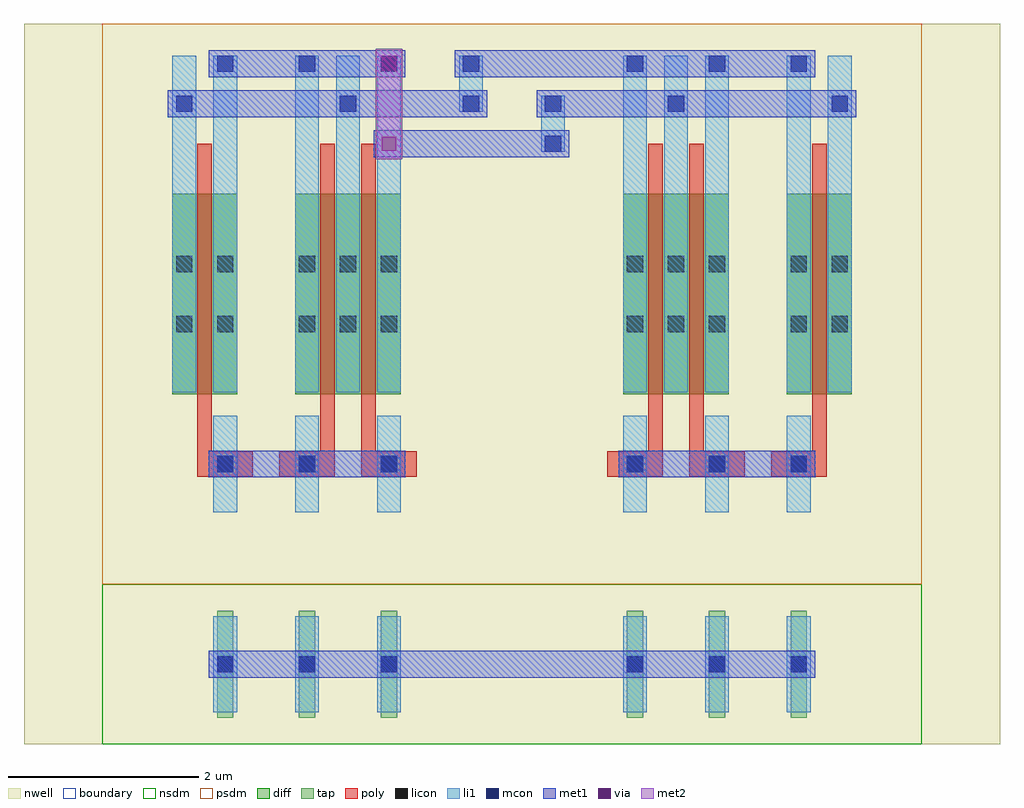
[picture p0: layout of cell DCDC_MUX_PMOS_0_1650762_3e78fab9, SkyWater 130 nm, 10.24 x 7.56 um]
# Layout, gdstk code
from math import pi, radians
import gdstk
lib = gdstk.Library(unit=1e-6, precision=1e-09)
def R(c, l, rs):  # rectangles x0, y0, x1, y1
    for r in rs: c.add(gdstk.rectangle(r[:2], r[2:], *l))
def A(c, l, x, y, w, h, nx, ny, dx, dy):  # array of equal rectangles
    R(c, l, [(x+i*dx, y+j*dy, x+i*dx+w, y+j*dy+h) for i in range(nx) for j in range(ny)])
def P(c, l, *ps):  # polygons
    for p in ps: c.add(gdstk.Polygon(p, *l))
nwell = (64, 20)
diff = (65, 20)
tap = (65, 44)
poly = (66, 20)
licon = (66, 44)
li1 = (67, 20)
mcon = (67, 44)
met1 = (68, 20)
via = (68, 44)
met2 = (69, 20)
nsdm = (93, 44)
psdm = (94, 20)
boundary = (235, 4)

pmos_4t_84335382_x3_y1__ = lib.new_cell('PMOS_4T_84335382_X3_Y1__e3cfcdb4')
R(pmos_4t_84335382_x3_y1__, nwell, [(0,0,5.12,7.56)])
R(pmos_4t_84335382_x3_y1__, diff, [(1.165,1.785,2.275,3.885), (2.885,1.785,3.565,3.885)])
A(pmos_4t_84335382_x3_y1__, tap, 1.205, 6.16, 0.17, 1.12, 3, 1, 0.86, 0)
A(pmos_4t_84335382_x3_y1__, poly, 1, 4.485, 0.58, 0.27, 3, 1, 0.86, 0)
R(pmos_4t_84335382_x3_y1__, poly, [(1.43,1.26,1.58,4.62), (1.86,1.26,2.01,4.62), (3.15,1.26,3.3,4.62)])
A(pmos_4t_84335382_x3_y1__, licon, 1.205, 4.535, 0.17, 0.17, 3, 2, 0.86, 2.1)
R(pmos_4t_84335382_x3_y1__, licon, [(1.205,2.435,1.375,2.605), (1.635,2.435,1.805,2.605), (1.635,2.435,1.805,2.605), (2.065,2.435,2.235,2.605), (2.925,2.435,3.095,2.605), (3.355,2.435,3.525,2.605), (1.205,3.065,1.375,3.235), (1.635,3.065,1.805,3.235), (1.635,3.065,1.805,3.235), (2.065,3.065,2.235,3.235), (2.925,3.065,3.095,3.235), (3.355,3.065,3.525,3.235)])
A(pmos_4t_84335382_x3_y1__, li1, 1.165, 0.335, 0.25, 3.53, 3, 1, 0.43, 0)
A(pmos_4t_84335382_x3_y1__, li1, 1.165, 4.115, 0.25, 1.01, 3, 2, 0.86, 2.1)
R(pmos_4t_84335382_x3_y1__, li1, [(2.885,0.335,3.135,3.865), (3.315,0.335,3.565,3.865)])
A(pmos_4t_84335382_x3_y1__, mcon, 1.205, 0.335, 0.17, 0.17, 3, 2, 0.86, 4.2)
A(pmos_4t_84335382_x3_y1__, mcon, 1.205, 6.635, 0.17, 0.17, 3, 1, 0.86, 0)
R(pmos_4t_84335382_x3_y1__, mcon, [(1.635,0.755,1.805,0.925), (3.355,0.755,3.525,0.925)])
R(pmos_4t_84335382_x3_y1__, met1, [(1.12,0.28,3.18,0.56), (0.69,0.7,3.61,0.98), (1.12,4.48,3.18,4.76), (1.12,6.58,3.18,6.86)])
R(pmos_4t_84335382_x3_y1__, nsdm, [(0,5.88,4.3,7.56)])
R(pmos_4t_84335382_x3_y1__, psdm, [(0,0,4.3,5.88)])

dcdc_mux_pmos_0_1650762_ = lib.new_cell('DCDC_MUX_PMOS_0_1650762_3e78fab9')
R(dcdc_mux_pmos_0_1650762_, li1, [(4.605,6.215,4.855,6.385), (4.605,6.215,4.855,6.385), (4.605,6.3,4.855,6.72), (3.745,6.635,3.995,6.805), (3.745,6.635,3.995,6.805), (4.605,6.635,4.855,6.805), (4.605,6.635,4.855,6.805), (3.745,6.72,3.995,7.14), (3.745,7.055,3.995,7.225), (3.745,7.055,3.995,7.225)])
R(dcdc_mux_pmos_0_1650762_, mcon, [(4.645,6.215,4.815,6.385), (4.645,6.215,4.815,6.385), (3.785,6.635,3.955,6.805), (3.785,6.635,3.955,6.805), (4.645,6.635,4.815,6.805), (4.645,6.635,4.815,6.805), (3.785,7.055,3.955,7.225), (3.785,7.055,3.955,7.225)])
R(dcdc_mux_pmos_0_1650762_, met1, [(3.01,0.7,5.59,0.98), (2.85,6.16,3.17,6.44), (2.85,6.16,3.17,6.44), (3.01,6.16,4.73,6.44), (4.56,6.16,4.9,6.44), (4.56,6.16,4.9,6.44), (3.44,6.58,3.87,6.86), (3.7,6.58,4.04,6.86), (3.7,6.58,4.04,6.86), (4.56,6.58,4.9,6.86), (4.56,6.58,4.9,6.86), (4.73,6.58,5.16,6.86), (2.85,7,3.17,7.28), (2.85,7,3.17,7.28), (3.7,7,4.04,7.28), (3.7,7,4.04,7.28), (3.87,7,5.59,7.28)])
P(dcdc_mux_pmos_0_1650762_, met1, [(0,0),(0,0),(0,0),(0,0)],
  [(0,0),(0,0),(0,0),(0,0)],
  [(0,0),(0,0),(0,0),(0,0)],
  [(0,0),(0,0),(0,0),(0,0)],
  [(0,0),(0,0),(0,0),(0,0)],
  [(0,0),(0,0),(0,0),(0,0)],
  [(0,0),(0,0),(0,0),(0,0)],
  [(0,0),(0,0),(0,0),(0,0)])
R(dcdc_mux_pmos_0_1650762_, via, [(2.935,6.225,3.085,6.375), (2.935,6.225,3.085,6.375), (2.935,7.065,3.085,7.215), (2.935,7.065,3.085,7.215)])
R(dcdc_mux_pmos_0_1650762_, met2, [(2.87,6.14,3.15,6.46), (2.87,6.14,3.15,6.46), (2.87,6.3,3.15,7.14), (2.87,6.98,3.15,7.3), (2.87,6.98,3.15,7.3)])
R(dcdc_mux_pmos_0_1650762_, boundary, [(0,0,8.6,7.56)])
dcdc_mux_pmos_0_1650762_.add(gdstk.Reference(pmos_4t_84335382_x3_y1__, (4.3,7.56), x_reflection=True))
dcdc_mux_pmos_0_1650762_.add(gdstk.Reference(pmos_4t_84335382_x3_y1__, (4.3,7.56), rotation=pi))

lib.write_gds('DCDC_MUX_PMOS_0_1650762_3e78fab9.gds')
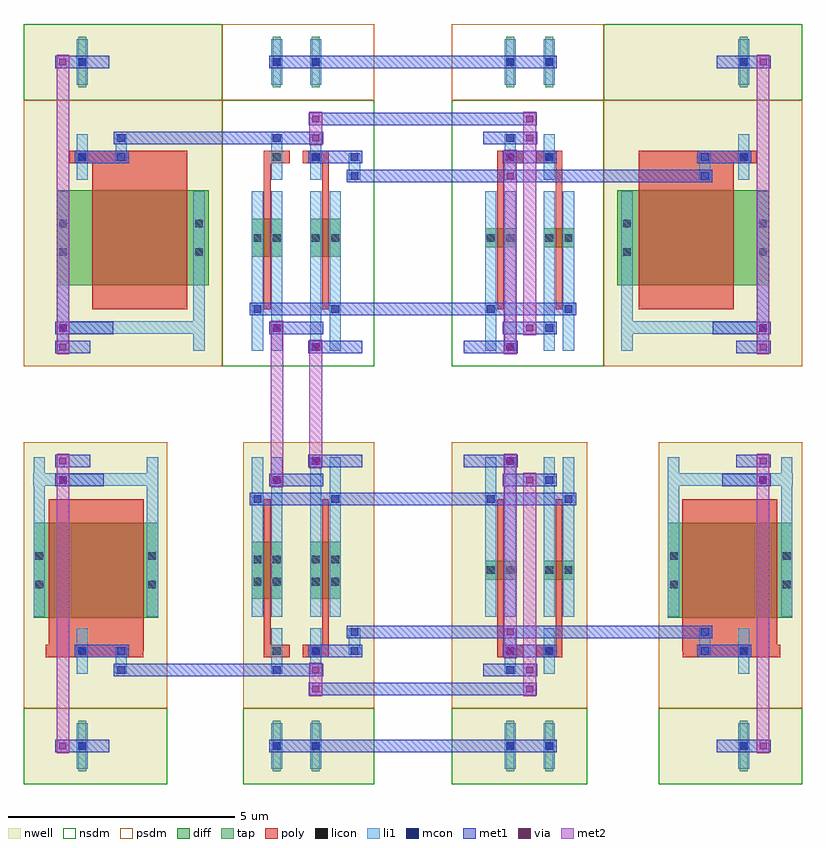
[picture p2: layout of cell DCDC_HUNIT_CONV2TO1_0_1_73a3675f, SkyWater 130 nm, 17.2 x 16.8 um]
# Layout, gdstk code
from math import pi, radians
import gdstk
lib = gdstk.Library(unit=1e-6, precision=1e-09)
def R(c, l, rs):  # rectangles x0, y0, x1, y1
    for r in rs: c.add(gdstk.rectangle(r[:2], r[2:], *l))
def P(c, l, *ps):  # polygons
    for p in ps: c.add(gdstk.Polygon(p, *l))
nwell = (64, 20)
diff = (65, 20)
tap = (65, 44)
poly = (66, 20)
licon = (66, 44)
li1 = (67, 20)
mcon = (67, 44)
met1 = (68, 20)
via = (68, 44)
met2 = (69, 20)
nsdm = (93, 44)
psdm = (94, 20)

ccp_pmos_b_88242555_x1__ = lib.new_cell('CCP_PMOS_B_88242555_X1__44b71c81')
R(ccp_pmos_b_88242555_x1__, nwell, [(0,0,2.99,7.56)])
R(ccp_pmos_b_88242555_x1__, diff, [(0.735,2.625,1.415,3.045), (2.025,2.625,2.705,3.045)])
R(ccp_pmos_b_88242555_x1__, tap, [(1.205,6.16,1.375,7.28), (2.065,6.16,2.235,7.28)])
R(ccp_pmos_b_88242555_x1__, poly, [(1,1.26,1.15,4.62), (2.29,1.26,2.44,4.62), (1,4.485,1.58,4.755), (1.86,4.485,2.44,4.755)])
R(ccp_pmos_b_88242555_x1__, licon, [(0.775,2.745,0.945,2.915), (1.205,2.745,1.375,2.915), (2.065,2.745,2.235,2.915), (2.495,2.745,2.665,2.915), (1.205,4.535,1.375,4.705), (2.065,4.535,2.235,4.705), (1.205,6.635,1.375,6.805), (2.065,6.635,2.235,6.805)])
R(ccp_pmos_b_88242555_x1__, li1, [(0.735,0.335,0.985,3.865), (1.165,0.335,1.415,3.865), (2.025,0.335,2.275,3.865), (2.455,0.335,2.705,3.865), (1.165,4.115,1.415,5.125), (2.025,4.115,2.275,5.125), (1.165,6.215,1.415,7.225), (2.025,6.215,2.275,7.225)])
R(ccp_pmos_b_88242555_x1__, mcon, [(1.205,0.335,1.375,0.505), (2.065,0.755,2.235,0.925), (0.775,1.175,0.945,1.345), (2.495,1.175,2.665,1.345), (2.065,4.535,2.235,4.705), (1.205,4.955,1.375,5.125), (1.205,6.635,1.375,6.805), (2.065,6.635,2.235,6.805)])
R(ccp_pmos_b_88242555_x1__, met1, [(0.26,0.28,1.46,0.56), (1.12,0.7,2.32,0.98), (0.69,1.12,2.75,1.4), (1.12,4.48,2.32,4.76), (0.69,4.9,1.89,5.18), (1.12,6.58,2.32,6.86)])
R(ccp_pmos_b_88242555_x1__, via, [(1.215,0.345,1.365,0.495), (1.645,0.765,1.795,0.915), (1.215,4.545,1.365,4.695), (1.645,4.965,1.795,5.115)])
R(ccp_pmos_b_88242555_x1__, met2, [(1.15,0.26,1.43,4.78), (1.58,0.68,1.86,5.2)])
R(ccp_pmos_b_88242555_x1__, nsdm, [(0,5.88,2.99,7.56)])
R(ccp_pmos_b_88242555_x1__, psdm, [(0,0,2.99,5.88)])

dp_pmos_b_25364157_x1_y_ = lib.new_cell('DP_PMOS_B_25364157_X1_Y_12b887c0')
R(dp_pmos_b_25364157_x1_y_, nwell, [(0,0,2.89,7.56)])
R(dp_pmos_b_25364157_x1_y_, diff, [(0.735,2.205,1.415,3.465), (2.025,2.205,2.705,3.465)])
R(dp_pmos_b_25364157_x1_y_, tap, [(1.205,6.16,1.375,7.28), (2.065,6.16,2.235,7.28)])
R(dp_pmos_b_25364157_x1_y_, poly, [(1,1.26,1.15,4.62), (2.29,1.26,2.44,4.62), (1,4.485,1.58,4.755), (1.86,4.485,2.44,4.755)])
R(dp_pmos_b_25364157_x1_y_, licon, [(0.775,2.515,0.945,2.685), (1.205,2.515,1.375,2.685), (2.065,2.515,2.235,2.685), (2.495,2.515,2.665,2.685), (0.775,3.005,0.945,3.175), (1.205,3.005,1.375,3.175), (2.065,3.005,2.235,3.175), (2.495,3.005,2.665,3.175), (1.205,4.535,1.375,4.705), (2.065,4.535,2.235,4.705), (1.205,6.635,1.375,6.805), (2.065,6.635,2.235,6.805)])
R(dp_pmos_b_25364157_x1_y_, li1, [(0.735,0.335,0.985,3.865), (1.165,0.335,1.415,3.865), (2.025,0.335,2.275,3.865), (2.455,0.335,2.705,3.865), (1.165,4.115,1.415,5.125), (2.025,4.115,2.275,5.125), (1.165,6.215,1.415,7.225), (2.025,6.215,2.275,7.225)])
R(dp_pmos_b_25364157_x1_y_, mcon, [(1.205,0.335,1.375,0.505), (2.065,0.755,2.235,0.925), (0.775,1.175,0.945,1.345), (2.495,1.175,2.665,1.345), (1.205,4.535,1.375,4.705), (2.065,4.955,2.235,5.125), (1.205,6.635,1.375,6.805), (2.065,6.635,2.235,6.805)])
R(dp_pmos_b_25364157_x1_y_, met1, [(0.26,0.28,1.46,0.56), (1.12,0.7,2.32,0.98), (0.69,1.12,2.75,1.4), (0.26,4.48,1.46,4.76), (1.12,4.9,2.32,5.18), (1.12,6.58,2.32,6.86)])
R(dp_pmos_b_25364157_x1_y_, nsdm, [(0,5.88,2.89,7.56)])
R(dp_pmos_b_25364157_x1_y_, psdm, [(0,0,2.89,5.88)])

dcap_pmos_98843368_x1_y_ = lib.new_cell('DCAP_PMOS_98843368_X1_Y_f9c0cc87')
R(dcap_pmos_98843368_x1_y_, nwell, [(-0.59,0,2.58,7.56)])
R(dcap_pmos_98843368_x1_y_, diff, [(-0.385,1.785,2.365,3.885)])
R(dcap_pmos_98843368_x1_y_, tap, [(1.205,6.16,1.375,7.28)])
R(dcap_pmos_98843368_x1_y_, poly, [(-0.065,1.26,2.035,4.62), (-0.06,4.485,2.1,4.755)])
R(dcap_pmos_98843368_x1_y_, licon, [(-0.335,2.435,-0.165,2.605), (2.155,2.435,2.325,2.605), (-0.335,3.065,-0.165,3.235), (2.155,3.065,2.325,3.235), (1.205,4.535,1.375,4.705), (1.205,6.635,1.375,6.805)])
R(dcap_pmos_98843368_x1_y_, li1, [(-0.385,0.335,-0.135,3.865), (2.115,0.335,2.365,3.865), (1.165,4.115,1.415,5.125), (1.165,6.215,1.415,7.225)])
R(dcap_pmos_98843368_x1_y_, mcon, [(1.635,0.755,1.805,0.925), (1.205,4.535,1.375,4.705), (1.205,6.635,1.375,6.805)])
R(dcap_pmos_98843368_x1_y_, met1, [(1.12,0.28,1.89,0.56), (0.82,0.7,1.89,0.98), (0.26,4.48,1.46,4.76), (0.69,6.58,1.89,6.86)])
R(dcap_pmos_98843368_x1_y_, via, [(1.645,0.345,1.795,0.495), (1.645,0.765,1.795,0.915), (1.645,6.645,1.795,6.795)])
R(dcap_pmos_98843368_x1_y_, met2, [(1.58,0.26,1.86,6.88)])
R(dcap_pmos_98843368_x1_y_, nsdm, [(-0.59,5.88,2.58,7.56)])
R(dcap_pmos_98843368_x1_y_, psdm, [(-0.59,0,2.58,5.88)])
dcap_pmos_98843368_x1_y_.add(gdstk.FlexPath([(-0.38,0.83),(2.37,0.83)], 0.28, ends="flush", simple_path=True, layer=67, datatype=20))  # li1

dcdc_xsw_pmos_0_1650326_ = lib.new_cell('DCDC_XSW_PMOS_0_1650326_40a43b21')
R(dcdc_xsw_pmos_0_1650326_, li1, [(7.185,4.115,7.435,4.285), (7.185,4.115,7.435,4.285), (7.185,4.115,7.435,4.285), (14.925,4.115,15.175,4.285), (14.925,4.115,15.175,4.285), (7.185,4.2,7.435,4.62), (14.925,4.2,15.175,4.62), (2.025,4.535,2.275,4.705), (2.025,4.535,2.275,4.705), (7.185,4.535,7.435,4.705), (7.185,4.535,7.435,4.705), (7.185,4.535,7.435,4.705), (14.925,4.535,15.175,4.705), (14.925,4.535,15.175,4.705), (2.025,4.62,2.275,5.04), (2.025,4.955,2.275,5.125), (2.025,4.955,2.275,5.125)])
R(dcdc_xsw_pmos_0_1650326_, mcon, [(7.225,4.115,7.395,4.285), (7.225,4.115,7.395,4.285), (7.225,4.115,7.395,4.285), (14.965,4.115,15.135,4.285), (14.965,4.115,15.135,4.285), (2.065,4.535,2.235,4.705), (2.065,4.535,2.235,4.705), (7.225,4.535,7.395,4.705), (7.225,4.535,7.395,4.705), (7.225,4.535,7.395,4.705), (14.965,4.535,15.135,4.705), (14.965,4.535,15.135,4.705), (2.065,4.955,2.235,5.125), (2.065,4.955,2.235,5.125)])
R(dcdc_xsw_pmos_0_1650326_, met1, [(6.88,1.12,10.32,1.4), (7.14,4.06,7.48,4.34), (7.14,4.06,7.48,4.34), (7.14,4.06,7.48,4.34), (7.31,4.06,10.75,4.34), (10.59,4.06,10.91,4.34), (10.59,4.06,10.91,4.34), (10.59,4.06,10.91,4.34), (10.75,4.06,15.05,4.34), (14.88,4.06,15.22,4.34), (14.88,4.06,15.22,4.34), (1.98,4.48,2.32,4.76), (1.98,4.48,2.32,4.76), (7.14,4.48,7.48,4.76), (7.14,4.48,7.48,4.76), (7.14,4.48,7.48,4.76), (14.88,4.48,15.22,4.76), (14.88,4.48,15.22,4.76), (1.98,4.9,2.32,5.18), (1.98,4.9,2.32,5.18), (2.15,4.9,5.59,5.18), (6.29,4.9,6.61,5.18), (6.29,4.9,6.61,5.18), (6.29,4.9,6.61,5.18), (6.29,5.32,6.61,5.6), (6.29,5.32,6.61,5.6), (6.29,5.32,6.61,5.6), (6.45,5.32,11.18,5.6), (11.02,5.32,11.34,5.6), (11.02,5.32,11.34,5.6), (11.02,5.32,11.34,5.6), (6.45,6.58,10.75,6.86)])
P(dcdc_xsw_pmos_0_1650326_, met1, [(0,0),(0,0),(0,0),(0,0)],
  [(0,0),(0,0),(0,0),(0,0)],
  [(0,0),(0,0),(0,0),(0,0)],
  [(0,0),(0,0),(0,0),(0,0)],
  [(0,0),(0,0),(0,0),(0,0)],
  [(0,0),(0,0),(0,0),(0,0)],
  [(0,0),(0,0),(0,0),(0,0)],
  [(0,0),(0,0),(0,0),(0,0)],
  [(0,0),(0,0),(0,0),(0,0)],
  [(0,0),(0,0),(0,0),(0,0)])
R(dcdc_xsw_pmos_0_1650326_, via, [(10.675,4.125,10.825,4.275), (10.675,4.125,10.825,4.275), (10.675,4.125,10.825,4.275), (6.375,4.965,6.525,5.115), (6.375,4.965,6.525,5.115), (6.375,4.965,6.525,5.115), (6.375,5.385,6.525,5.535), (6.375,5.385,6.525,5.535), (6.375,5.385,6.525,5.535), (11.105,5.385,11.255,5.535), (11.105,5.385,11.255,5.535), (11.105,5.385,11.255,5.535)])
R(dcdc_xsw_pmos_0_1650326_, met2, [(10.61,4.04,10.89,4.36), (10.61,4.04,10.89,4.36), (10.61,4.04,10.89,4.36), (6.31,4.88,6.59,5.2), (6.31,4.88,6.59,5.2), (6.31,4.88,6.59,5.2), (6.31,5.04,6.59,5.46), (11.04,5.04,11.32,5.46), (6.31,5.3,6.59,5.62), (6.31,5.3,6.59,5.62), (6.31,5.3,6.59,5.62), (11.04,5.3,11.32,5.62), (11.04,5.3,11.32,5.62), (11.04,5.3,11.32,5.62)])
P(dcdc_xsw_pmos_0_1650326_, met2, [(0,0),(0,0),(0,0),(0,0)],
  [(0,0),(0,0),(0,0),(0,0)],
  [(0,0),(0,0),(0,0),(0,0)],
  [(0,0),(0,0),(0,0),(0,0)])
dcdc_xsw_pmos_0_1650326_.add(gdstk.Reference(ccp_pmos_b_88242555_x1__, (9.46,0)))
dcdc_xsw_pmos_0_1650326_.add(gdstk.Reference(dp_pmos_b_25364157_x1_y_, (7.74,0), rotation=pi, x_reflection=True))
dcdc_xsw_pmos_0_1650326_.add(gdstk.Reference(dcap_pmos_98843368_x1_y_, (14.62,0)))
dcdc_xsw_pmos_0_1650326_.add(gdstk.Reference(dcap_pmos_98843368_x1_y_, (2.58,0), rotation=pi, x_reflection=True))

ccp_nmos_b_82699349_x1__ = lib.new_cell('CCP_NMOS_B_82699349_X1__3a37f603')
R(ccp_nmos_b_82699349_x1__, diff, [(0.735,2.625,1.415,3.045), (2.025,2.625,2.705,3.045)])
R(ccp_nmos_b_82699349_x1__, tap, [(1.205,6.16,1.375,7.28), (2.065,6.16,2.235,7.28)])
R(ccp_nmos_b_82699349_x1__, poly, [(1,1.26,1.15,4.62), (2.29,1.26,2.44,4.62), (1,4.485,1.58,4.755), (1.86,4.485,2.44,4.755)])
R(ccp_nmos_b_82699349_x1__, licon, [(0.775,2.745,0.945,2.915), (0.775,2.745,0.945,2.915), (1.205,2.745,1.375,2.915), (2.065,2.745,2.235,2.915), (2.495,2.745,2.665,2.915), (1.205,4.535,1.375,4.705), (2.065,4.535,2.235,4.705), (1.205,6.635,1.375,6.805), (2.065,6.635,2.235,6.805)])
R(ccp_nmos_b_82699349_x1__, li1, [(0.735,0.335,0.985,3.865), (1.165,0.335,1.415,3.865), (2.025,0.335,2.275,3.865), (2.455,0.335,2.705,3.865), (1.165,4.115,1.415,5.125), (2.025,4.115,2.275,5.125), (1.165,6.215,1.415,7.225), (2.025,6.215,2.275,7.225)])
R(ccp_nmos_b_82699349_x1__, mcon, [(1.205,0.335,1.375,0.505), (2.065,0.755,2.235,0.925), (0.775,1.175,0.945,1.345), (2.495,1.175,2.665,1.345), (2.065,4.535,2.235,4.705), (1.205,4.955,1.375,5.125), (1.205,6.635,1.375,6.805), (2.065,6.635,2.235,6.805)])
R(ccp_nmos_b_82699349_x1__, met1, [(0.26,0.28,1.46,0.56), (1.12,0.7,2.32,0.98), (0.69,1.12,2.75,1.4), (1.12,4.48,2.32,4.76), (0.69,4.9,1.89,5.18), (1.12,6.58,2.32,6.86)])
R(ccp_nmos_b_82699349_x1__, via, [(1.215,0.345,1.365,0.495), (1.645,0.765,1.795,0.915), (1.215,4.545,1.365,4.695), (1.645,4.965,1.795,5.115)])
R(ccp_nmos_b_82699349_x1__, met2, [(1.15,0.26,1.43,4.78), (1.58,0.68,1.86,5.2)])
R(ccp_nmos_b_82699349_x1__, nsdm, [(0,0,3.36,5.88)])
R(ccp_nmos_b_82699349_x1__, psdm, [(0,5.88,3.36,7.56)])

dp_nmos_b_83449181_x1_y_ = lib.new_cell('DP_NMOS_B_83449181_X1_Y_edeae765')
R(dp_nmos_b_83449181_x1_y_, diff, [(0.735,2.415,1.415,3.255), (2.025,2.415,2.705,3.255)])
R(dp_nmos_b_83449181_x1_y_, tap, [(1.205,6.16,1.375,7.28), (2.065,6.16,2.235,7.28)])
R(dp_nmos_b_83449181_x1_y_, poly, [(1,1.26,1.15,4.62), (2.29,1.26,2.44,4.62), (1,4.485,1.58,4.755), (1.86,4.485,2.44,4.755)])
R(dp_nmos_b_83449181_x1_y_, licon, [(0.775,2.745,0.945,2.915), (1.205,2.745,1.375,2.915), (2.065,2.745,2.235,2.915), (2.495,2.745,2.665,2.915), (1.205,4.535,1.375,4.705), (2.065,4.535,2.235,4.705), (1.205,6.635,1.375,6.805), (2.065,6.635,2.235,6.805)])
R(dp_nmos_b_83449181_x1_y_, li1, [(0.735,0.335,0.985,3.865), (1.165,0.335,1.415,3.865), (2.025,0.335,2.275,3.865), (2.455,0.335,2.705,3.865), (1.165,4.115,1.415,5.125), (2.025,4.115,2.275,5.125), (1.165,6.215,1.415,7.225), (2.025,6.215,2.275,7.225)])
R(dp_nmos_b_83449181_x1_y_, mcon, [(1.205,0.335,1.375,0.505), (2.065,0.755,2.235,0.925), (0.775,1.175,0.945,1.345), (2.495,1.175,2.665,1.345), (1.205,4.535,1.375,4.705), (2.065,4.955,2.235,5.125), (1.205,6.635,1.375,6.805), (2.065,6.635,2.235,6.805)])
R(dp_nmos_b_83449181_x1_y_, met1, [(0.26,0.28,1.46,0.56), (1.12,0.7,2.32,0.98), (0.69,1.12,2.75,1.4), (0.26,4.48,1.46,4.76), (1.12,4.9,2.32,5.18), (1.12,6.58,2.32,6.86)])
R(dp_nmos_b_83449181_x1_y_, nsdm, [(0,0,3.36,5.88)])
R(dp_nmos_b_83449181_x1_y_, psdm, [(0,5.88,3.36,7.56)])

c_dcap_pmos_98843368_x1_y_ = lib.new_cell('DCAP_PMOS_98843368_X1_Y_1407ea6c')
R(c_dcap_pmos_98843368_x1_y_, nwell, [(-1.8,0,2.58,7.56)])
R(c_dcap_pmos_98843368_x1_y_, diff, [(-1.505,1.785,1.845,3.885)])
R(c_dcap_pmos_98843368_x1_y_, tap, [(1.205,6.16,1.375,7.28)])
R(c_dcap_pmos_98843368_x1_y_, poly, [(-1.025,1.26,1.075,4.62), (-1.03,4.485,1.58,4.755)])
R(c_dcap_pmos_98843368_x1_y_, licon, [(-1.375,2.435,-1.205,2.605), (1.635,2.435,1.805,2.605), (-1.375,3.065,-1.205,3.235), (1.635,3.065,1.805,3.235), (1.205,4.535,1.375,4.705), (1.205,6.635,1.375,6.805)])
R(c_dcap_pmos_98843368_x1_y_, li1, [(-1.415,0.335,-1.165,3.865), (1.595,0.335,1.845,3.865), (1.165,4.115,1.415,5.125), (1.165,6.215,1.415,7.225)])
R(c_dcap_pmos_98843368_x1_y_, mcon, [(1.635,0.755,1.805,0.925), (1.205,4.535,1.375,4.705), (1.205,6.635,1.375,6.805)])
R(c_dcap_pmos_98843368_x1_y_, met1, [(1.12,0.28,1.89,0.56), (0.61,0.7,1.89,0.98), (0.26,4.48,1.46,4.76), (0.69,6.58,1.89,6.86)])
R(c_dcap_pmos_98843368_x1_y_, via, [(1.645,0.345,1.795,0.495), (1.645,0.765,1.795,0.915), (1.645,6.645,1.795,6.795)])
R(c_dcap_pmos_98843368_x1_y_, met2, [(1.58,0.26,1.86,6.88)])
R(c_dcap_pmos_98843368_x1_y_, nsdm, [(-1.8,5.88,2.58,7.56)])
R(c_dcap_pmos_98843368_x1_y_, psdm, [(-1.8,0,2.58,5.88)])
c_dcap_pmos_98843368_x1_y_.add(gdstk.FlexPath([(-1.25,0.85),(1.84,0.85)], 0.28, ends="flush", simple_path=True, layer=67, datatype=20))  # li1

dcdc_xsw_nmos_0_1650326_ = lib.new_cell('DCDC_XSW_NMOS_0_1650326_24c8b01c')
R(dcdc_xsw_nmos_0_1650326_, li1, [(7.185,4.115,7.435,4.285), (7.185,4.115,7.435,4.285), (7.185,4.115,7.435,4.285), (14.925,4.115,15.175,4.285), (14.925,4.115,15.175,4.285), (7.185,4.2,7.435,4.62), (14.925,4.2,15.175,4.62), (2.025,4.535,2.275,4.705), (2.025,4.535,2.275,4.705), (7.185,4.535,7.435,4.705), (7.185,4.535,7.435,4.705), (7.185,4.535,7.435,4.705), (14.925,4.535,15.175,4.705), (14.925,4.535,15.175,4.705), (2.025,4.62,2.275,5.04), (2.025,4.955,2.275,5.125), (2.025,4.955,2.275,5.125)])
R(dcdc_xsw_nmos_0_1650326_, mcon, [(7.225,4.115,7.395,4.285), (7.225,4.115,7.395,4.285), (7.225,4.115,7.395,4.285), (14.965,4.115,15.135,4.285), (14.965,4.115,15.135,4.285), (2.065,4.535,2.235,4.705), (2.065,4.535,2.235,4.705), (7.225,4.535,7.395,4.705), (7.225,4.535,7.395,4.705), (7.225,4.535,7.395,4.705), (14.965,4.535,15.135,4.705), (14.965,4.535,15.135,4.705), (2.065,4.955,2.235,5.125), (2.065,4.955,2.235,5.125)])
R(dcdc_xsw_nmos_0_1650326_, met1, [(6.88,1.12,10.32,1.4), (7.14,4.06,7.48,4.34), (7.14,4.06,7.48,4.34), (7.14,4.06,7.48,4.34), (7.31,4.06,10.75,4.34), (10.59,4.06,10.91,4.34), (10.59,4.06,10.91,4.34), (10.59,4.06,10.91,4.34), (10.75,4.06,15.05,4.34), (14.88,4.06,15.22,4.34), (14.88,4.06,15.22,4.34), (1.98,4.48,2.32,4.76), (1.98,4.48,2.32,4.76), (7.14,4.48,7.48,4.76), (7.14,4.48,7.48,4.76), (7.14,4.48,7.48,4.76), (14.88,4.48,15.22,4.76), (14.88,4.48,15.22,4.76), (1.98,4.9,2.32,5.18), (1.98,4.9,2.32,5.18), (2.15,4.9,5.59,5.18), (6.29,4.9,6.61,5.18), (6.29,4.9,6.61,5.18), (6.29,4.9,6.61,5.18), (6.29,5.32,6.61,5.6), (6.29,5.32,6.61,5.6), (6.29,5.32,6.61,5.6), (6.45,5.32,11.18,5.6), (11.02,5.32,11.34,5.6), (11.02,5.32,11.34,5.6), (11.02,5.32,11.34,5.6), (6.45,6.58,10.75,6.86)])
P(dcdc_xsw_nmos_0_1650326_, met1, [(0,0),(0,0),(0,0),(0,0)],
  [(0,0),(0,0),(0,0),(0,0)],
  [(0,0),(0,0),(0,0),(0,0)],
  [(0,0),(0,0),(0,0),(0,0)],
  [(0,0),(0,0),(0,0),(0,0)],
  [(0,0),(0,0),(0,0),(0,0)],
  [(0,0),(0,0),(0,0),(0,0)],
  [(0,0),(0,0),(0,0),(0,0)],
  [(0,0),(0,0),(0,0),(0,0)],
  [(0,0),(0,0),(0,0),(0,0)])
R(dcdc_xsw_nmos_0_1650326_, via, [(10.675,4.125,10.825,4.275), (10.675,4.125,10.825,4.275), (10.675,4.125,10.825,4.275), (6.375,4.965,6.525,5.115), (6.375,4.965,6.525,5.115), (6.375,4.965,6.525,5.115), (6.375,5.385,6.525,5.535), (6.375,5.385,6.525,5.535), (6.375,5.385,6.525,5.535), (11.105,5.385,11.255,5.535), (11.105,5.385,11.255,5.535), (11.105,5.385,11.255,5.535)])
R(dcdc_xsw_nmos_0_1650326_, met2, [(10.61,4.04,10.89,4.36), (10.61,4.04,10.89,4.36), (10.61,4.04,10.89,4.36), (6.31,4.88,6.59,5.2), (6.31,4.88,6.59,5.2), (6.31,4.88,6.59,5.2), (6.31,5.04,6.59,5.46), (11.04,5.04,11.32,5.46), (6.31,5.3,6.59,5.62), (6.31,5.3,6.59,5.62), (6.31,5.3,6.59,5.62), (11.04,5.3,11.32,5.62), (11.04,5.3,11.32,5.62), (11.04,5.3,11.32,5.62)])
P(dcdc_xsw_nmos_0_1650326_, met2, [(0,0),(0,0),(0,0),(0,0)],
  [(0,0),(0,0),(0,0),(0,0)],
  [(0,0),(0,0),(0,0),(0,0)],
  [(0,0),(0,0),(0,0),(0,0)])
dcdc_xsw_nmos_0_1650326_.add(gdstk.Reference(ccp_nmos_b_82699349_x1__, (9.46,0)))
dcdc_xsw_nmos_0_1650326_.add(gdstk.Reference(dp_nmos_b_83449181_x1_y_, (7.74,0), rotation=pi, x_reflection=True))
dcdc_xsw_nmos_0_1650326_.add(gdstk.Reference(c_dcap_pmos_98843368_x1_y_, (14.62,0)))
dcdc_xsw_nmos_0_1650326_.add(gdstk.Reference(c_dcap_pmos_98843368_x1_y_, (2.58,0), rotation=pi, x_reflection=True))

dcdc_hunit_conv2to1_0_1_ = lib.new_cell('DCDC_HUNIT_CONV2TO1_0_1_73a3675f')
R(dcdc_hunit_conv2to1_0_1_, met1, [(5.43,6.58,5.75,6.86), (5.43,6.58,5.75,6.86), (6.29,7,6.61,7.28), (6.29,7,6.61,7.28), (6.29,9.52,6.61,9.8), (6.29,9.52,6.61,9.8), (5.43,9.94,5.75,10.22), (5.43,9.94,5.75,10.22)])
P(dcdc_hunit_conv2to1_0_1_, met1, [(0,0),(0,0),(0,0),(0,0)],
  [(0,0),(0,0),(0,0),(0,0)],
  [(0,0),(0,0),(0,0),(0,0)],
  [(0,0),(0,0),(0,0),(0,0)],
  [(0,0),(0,0),(0,0),(0,0)],
  [(0,0),(0,0),(0,0),(0,0)],
  [(0,0),(0,0),(0,0),(0,0)],
  [(0,0),(0,0),(0,0),(0,0)],
  [(0,0),(0,0),(0,0),(0,0)],
  [(0,0),(0,0),(0,0),(0,0)],
  [(0,0),(0,0),(0,0),(0,0)],
  [(0,0),(0,0),(0,0),(0,0)],
  [(0,0),(0,0),(0,0),(0,0)],
  [(0,0),(0,0),(0,0),(0,0)],
  [(0,0),(0,0),(0,0),(0,0)],
  [(0,0),(0,0),(0,0),(0,0)])
R(dcdc_hunit_conv2to1_0_1_, via, [(5.515,6.645,5.665,6.795), (5.515,6.645,5.665,6.795), (6.375,7.065,6.525,7.215), (6.375,7.065,6.525,7.215), (6.375,9.585,6.525,9.735), (6.375,9.585,6.525,9.735), (5.515,10.005,5.665,10.155), (5.515,10.005,5.665,10.155)])
R(dcdc_hunit_conv2to1_0_1_, met2, [(5.45,6.56,5.73,6.88), (5.45,6.56,5.73,6.88), (5.45,6.72,5.73,10.08), (6.31,6.98,6.59,7.3), (6.31,6.98,6.59,7.3), (6.31,7.14,6.59,9.66), (6.31,9.5,6.59,9.82), (6.31,9.5,6.59,9.82), (5.45,9.92,5.73,10.24), (5.45,9.92,5.73,10.24)])
P(dcdc_hunit_conv2to1_0_1_, met2, [(0,0),(0,0),(0,0),(0,0)],
  [(0,0),(0,0),(0,0),(0,0)],
  [(0,0),(0,0),(0,0),(0,0)],
  [(0,0),(0,0),(0,0),(0,0)])
dcdc_hunit_conv2to1_0_1_.add(gdstk.Reference(dcdc_xsw_pmos_0_1650326_, (0,7.56), x_reflection=True))
dcdc_hunit_conv2to1_0_1_.add(gdstk.Reference(dcdc_xsw_nmos_0_1650326_, (0,9.24)))

lib.write_gds('DCDC_HUNIT_CONV2TO1_0_1_73a3675f.gds')
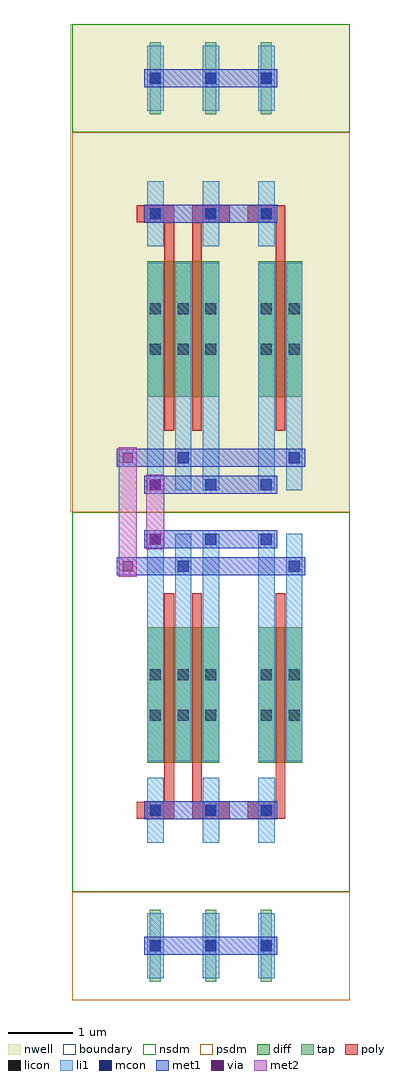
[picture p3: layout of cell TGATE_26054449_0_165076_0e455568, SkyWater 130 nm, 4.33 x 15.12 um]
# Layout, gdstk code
import gdstk
lib = gdstk.Library(unit=1e-6, precision=1e-09)
def R(c, l, rs):  # rectangles x0, y0, x1, y1
    for r in rs: c.add(gdstk.rectangle(r[:2], r[2:], *l))
def A(c, l, x, y, w, h, nx, ny, dx, dy):  # array of equal rectangles
    R(c, l, [(x+i*dx, y+j*dy, x+i*dx+w, y+j*dy+h) for i in range(nx) for j in range(ny)])
def P(c, l, *ps):  # polygons
    for p in ps: c.add(gdstk.Polygon(p, *l))
nwell = (64, 20)
diff = (65, 20)
tap = (65, 44)
poly = (66, 20)
licon = (66, 44)
li1 = (67, 20)
mcon = (67, 44)
met1 = (68, 20)
via = (68, 44)
met2 = (69, 20)
nsdm = (93, 44)
psdm = (94, 20)
boundary = (235, 4)

nmos_4t_23806256_x3_y1__ = lib.new_cell('NMOS_4T_23806256_X3_Y1__034001d7')
R(nmos_4t_23806256_x3_y1__, diff, [(1.165,1.785,2.275,3.885), (2.885,1.785,3.565,3.885)])
A(nmos_4t_23806256_x3_y1__, tap, 1.205, 6.16, 0.17, 1.12, 3, 1, 0.86, 0)
A(nmos_4t_23806256_x3_y1__, poly, 1, 4.485, 0.58, 0.27, 3, 1, 0.86, 0)
R(nmos_4t_23806256_x3_y1__, poly, [(1.43,1.26,1.58,4.62), (1.86,1.26,2.01,4.62), (3.15,1.26,3.3,4.62)])
A(nmos_4t_23806256_x3_y1__, licon, 1.205, 4.535, 0.17, 0.17, 3, 2, 0.86, 2.1)
R(nmos_4t_23806256_x3_y1__, licon, [(1.205,2.435,1.375,2.605), (1.635,2.435,1.805,2.605), (1.635,2.435,1.805,2.605), (2.065,2.435,2.235,2.605), (2.925,2.435,3.095,2.605), (3.355,2.435,3.525,2.605), (1.205,3.065,1.375,3.235), (1.635,3.065,1.805,3.235), (1.635,3.065,1.805,3.235), (2.065,3.065,2.235,3.235), (2.925,3.065,3.095,3.235), (3.355,3.065,3.525,3.235)])
A(nmos_4t_23806256_x3_y1__, li1, 1.165, 0.335, 0.25, 3.53, 3, 1, 0.43, 0)
A(nmos_4t_23806256_x3_y1__, li1, 1.165, 4.115, 0.25, 1.01, 3, 2, 0.86, 2.1)
R(nmos_4t_23806256_x3_y1__, li1, [(2.885,0.335,3.135,3.865), (3.315,0.335,3.565,3.865)])
A(nmos_4t_23806256_x3_y1__, mcon, 1.205, 0.335, 0.17, 0.17, 3, 2, 0.86, 4.2)
A(nmos_4t_23806256_x3_y1__, mcon, 1.205, 6.635, 0.17, 0.17, 3, 1, 0.86, 0)
R(nmos_4t_23806256_x3_y1__, mcon, [(1.635,0.755,1.805,0.925), (3.355,0.755,3.525,0.925)])
R(nmos_4t_23806256_x3_y1__, met1, [(1.12,0.28,3.18,0.56), (0.69,0.7,3.61,0.98), (1.12,4.48,3.18,4.76), (1.12,6.58,3.18,6.86)])
R(nmos_4t_23806256_x3_y1__, nsdm, [(0,0,4.3,5.88)])
R(nmos_4t_23806256_x3_y1__, psdm, [(0,5.88,4.3,7.56)])

pmos_4t_84335382_x3_y1__ = lib.new_cell('PMOS_4T_84335382_X3_Y1__f7f60cb8')
R(pmos_4t_84335382_x3_y1__, nwell, [(-0.03,0,4.3,7.56)])
R(pmos_4t_84335382_x3_y1__, diff, [(1.165,1.785,2.275,3.885), (2.885,1.785,3.565,3.885)])
A(pmos_4t_84335382_x3_y1__, tap, 1.205, 6.16, 0.17, 1.12, 3, 1, 0.86, 0)
A(pmos_4t_84335382_x3_y1__, poly, 1, 4.485, 0.58, 0.27, 3, 1, 0.86, 0)
R(pmos_4t_84335382_x3_y1__, poly, [(1.43,1.26,1.58,4.62), (1.86,1.26,2.01,4.62), (3.15,1.26,3.3,4.62)])
A(pmos_4t_84335382_x3_y1__, licon, 1.205, 4.535, 0.17, 0.17, 3, 2, 0.86, 2.1)
R(pmos_4t_84335382_x3_y1__, licon, [(1.205,2.435,1.375,2.605), (1.635,2.435,1.805,2.605), (1.635,2.435,1.805,2.605), (2.065,2.435,2.235,2.605), (2.925,2.435,3.095,2.605), (3.355,2.435,3.525,2.605), (1.205,3.065,1.375,3.235), (1.635,3.065,1.805,3.235), (1.635,3.065,1.805,3.235), (2.065,3.065,2.235,3.235), (2.925,3.065,3.095,3.235), (3.355,3.065,3.525,3.235)])
A(pmos_4t_84335382_x3_y1__, li1, 1.165, 0.335, 0.25, 3.53, 3, 1, 0.43, 0)
A(pmos_4t_84335382_x3_y1__, li1, 1.165, 4.115, 0.25, 1.01, 3, 2, 0.86, 2.1)
R(pmos_4t_84335382_x3_y1__, li1, [(2.885,0.335,3.135,3.865), (3.315,0.335,3.565,3.865)])
A(pmos_4t_84335382_x3_y1__, mcon, 1.205, 0.335, 0.17, 0.17, 3, 2, 0.86, 4.2)
A(pmos_4t_84335382_x3_y1__, mcon, 1.205, 6.635, 0.17, 0.17, 3, 1, 0.86, 0)
R(pmos_4t_84335382_x3_y1__, mcon, [(1.635,0.755,1.805,0.925), (3.355,0.755,3.525,0.925)])
R(pmos_4t_84335382_x3_y1__, met1, [(1.12,0.28,3.18,0.56), (0.69,0.7,3.61,0.98), (1.12,4.48,3.18,4.76), (1.12,6.58,3.18,6.86)])
R(pmos_4t_84335382_x3_y1__, nsdm, [(0,5.88,4.3,7.56)])
R(pmos_4t_84335382_x3_y1__, psdm, [(0,0,4.3,5.88)])

tgate_26054449_0_165076_ = lib.new_cell('TGATE_26054449_0_165076_0e455568')
R(tgate_26054449_0_165076_, met1, [(0.7,6.58,1.02,6.86), (0.7,6.58,1.02,6.86), (1.13,7,1.45,7.28), (1.13,7,1.45,7.28), (1.13,7.84,1.45,8.12), (1.13,7.84,1.45,8.12), (0.7,8.26,1.02,8.54), (0.7,8.26,1.02,8.54)])
P(tgate_26054449_0_165076_, met1, [(0,0),(0,0),(0,0),(0,0)],
  [(0,0),(0,0),(0,0),(0,0)],
  [(0,0),(0,0),(0,0),(0,0)],
  [(0,0),(0,0),(0,0),(0,0)],
  [(0,0),(0,0),(0,0),(0,0)],
  [(0,0),(0,0),(0,0),(0,0)],
  [(0,0),(0,0),(0,0),(0,0)],
  [(0,0),(0,0),(0,0),(0,0)])
R(tgate_26054449_0_165076_, via, [(0.785,6.645,0.935,6.795), (0.785,6.645,0.935,6.795), (1.215,7.065,1.365,7.215), (1.215,7.065,1.365,7.215), (1.215,7.905,1.365,8.055), (1.215,7.905,1.365,8.055), (0.785,8.325,0.935,8.475), (0.785,8.325,0.935,8.475)])
R(tgate_26054449_0_165076_, met2, [(0.72,6.56,1,6.88), (0.72,6.56,1,6.88), (0.72,6.72,1,8.4), (1.15,6.98,1.43,7.3), (1.15,6.98,1.43,7.3), (1.15,7.14,1.43,7.98), (1.15,7.82,1.43,8.14), (1.15,7.82,1.43,8.14), (0.72,8.24,1,8.56), (0.72,8.24,1,8.56)])
R(tgate_26054449_0_165076_, boundary, [(0,0,4.3,15.12)])
tgate_26054449_0_165076_.add(gdstk.Reference(nmos_4t_23806256_x3_y1__, (0,7.56), x_reflection=True))
tgate_26054449_0_165076_.add(gdstk.Reference(pmos_4t_84335382_x3_y1__, (0,7.56)))

lib.write_gds('TGATE_26054449_0_165076_0e455568.gds')
